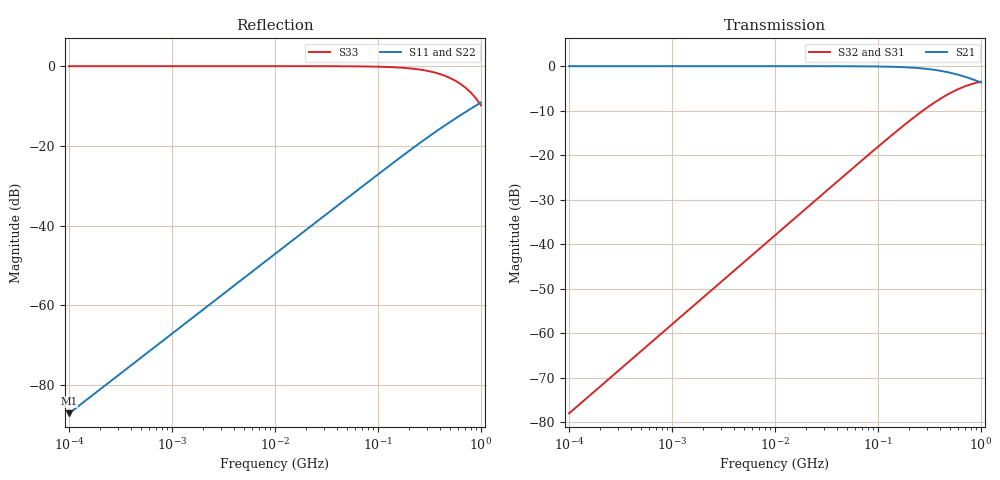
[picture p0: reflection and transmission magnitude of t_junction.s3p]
# Hz S RI R 50
! golden: t_junction
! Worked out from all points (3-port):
!   81 points, 100 kHz to 1 GHz, reference 50 ohm
!   strongest paths, dB at 100 kHz, 1 MHz, 10 MHz, 100 MHz, 1 GHz:
!     S21: 0.0, 0.0, 0.0, -0.1, -3.7
!     S32: -78.0, -58.0, -38.0, -18.1, -3.5
!     S31: -78.0, -58.0, -38.0, -18.1, -3.5
!   lowest |S11| = -87.1 dB at 100 kHz (marker M1), VSWR 1.00, Z = 50 - j0.0044 ohm
!   |S11| at or under -10 dB: start of sweep to 880.6 MHz
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100000  -6.15e-08 -4.4e-05  1 -8.17e-05  1.58e-08 0.000126
        1 -8.17e-05  -6.15e-08 -4.4e-05  1.58e-08 0.000126
        1.58e-08 0.000126  1.58e-08 0.000126  1 -0.000126
223872.1  -1.08e-07 -9.85e-05  1 -0.000183  7.91e-08 0.000281
          1 -0.000183  -1.08e-07 -9.85e-05  7.91e-08 0.000281
          7.91e-08 0.000281  7.91e-08 0.000281  1 -0.000281
1e7  -0.000115 -0.0044  0.9999 -0.00817  0.000158 0.0126
     0.9999 -0.00817  -0.000115 -0.0044  0.000158 0.0126
     0.000158 0.0126  0.000158 0.0126  0.9998 -0.0126
6.309573e7  -0.00453 -0.0273  0.9952 -0.0511  0.00623 0.0787
            0.9952 -0.0511  -0.00453 -0.0273  0.00623 0.0787
            0.00623 0.0787  0.00623 0.0787  0.9907 -0.0784
1.258925e8  -0.0176 -0.052  0.9813 -0.0995  0.0241 0.1534
            0.9813 -0.0995  -0.0176 -0.052  0.0241 0.1534
            0.0241 0.1534  0.0241 0.1534  0.9637 -0.1515
1.995262e8  -0.0419 -0.075  0.9553 -0.1505  0.0574 0.2327
            0.9553 -0.1505  -0.0419 -0.075  0.0574 0.2327
            0.0574 0.2327  0.0574 0.2327  0.9134 -0.2255
3.548134e8  -0.1119 -0.0953  0.8789 -0.2305  0.1528 0.3598
            0.8789 -0.2305  -0.1119 -0.0953  0.1528 0.3598
            0.1528 0.3598  0.1528 0.3598  0.7669 -0.3258
5.623413e8  -0.2091 -0.0664  0.7669 -0.284  0.283 0.4504
            0.7669 -0.284  -0.2091 -0.0664  0.283 0.4504
            0.283 0.4504  0.283 0.4504  0.5579 -0.3505
7.943282e8  -0.291 0.0111  0.6579 -0.3043  0.3897 0.4877
            0.6579 -0.3043  -0.291 0.0111  0.3897 0.4877
            0.3897 0.4877  0.3897 0.4877  0.3669 -0.2932
1e9  -0.3365 0.0966  0.576 -0.3124  0.448 0.4973
     0.576 -0.3124  -0.3365 0.0966  0.448 0.4973
     0.448 0.4973  0.448 0.4973  0.2395 -0.2158
